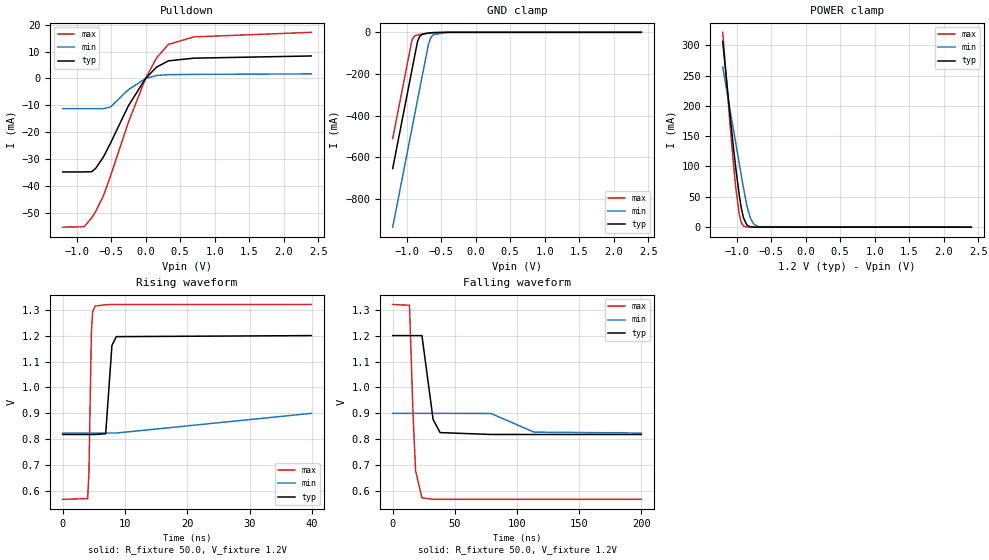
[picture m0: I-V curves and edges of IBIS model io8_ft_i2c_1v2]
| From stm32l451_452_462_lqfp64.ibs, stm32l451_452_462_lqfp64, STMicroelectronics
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[Model]   io8_ft_i2c_1v2
Model_type I/O_open_drain
Polarity   Non-Inverting
Enable   Active-Low
| CAP_THRESHOLD on pad IOFT is "UDTCAPC" :
| Rising=30.00f vddiom   Falling=70.00f vddiom
| C_comp min and max val. don't necessarily correlate with the min and max pvt
| but are the smallest and greatest pad capacitance found.
| var   typ   min   max
C_comp   1.98220pF  1.85370pF  1.99115pF
|C_comp_pulldown   1.98220pF  1.85370pF  1.99115pF
Vinl = 270.0mV
Vinh = 924.0mV
Vmeas = 600.0mV   | Reference voltage for timing measurements
Cref  = 50.0pF   | Timing specification test load capacitance value
Rref  = 100.0MOhm   | Timing specification test load resistance value
Vref  = 1100.0mV   | Timing specification test load voltage
[Model Spec]
| TIME_THRESHOLD on pin ZIV12 is "CMOS" :
| Rising=50.00f vdd   Falling=50.00f vdd
Vinl 458.70000mV 364.70000mV 499.70000mV
Vinh 728.30000mV 548.30000mV 792.30000mV
| variable   typ   min   max
[Temperature Range] 25.0 140.0 -40.0
| variable   typ   min   max
[Voltage Range] 1.2V 900.0mV 1.32V
| variable   typ   min   max
[POWER Clamp Reference] 1.2V 900.0mV 1.32V
| variable   typ   min   max
[GND Clamp Reference] 0V 0V 0V
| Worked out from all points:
|   slope of the pulldown table from 0 to 0.18 V, typ, clamps not added: 39.2 ohm
|   GND clamp passes 1 mA (typ) near -0.58 V on its own axis
|   POWER clamp passes 1 mA (typ) near -0.81 V on its own axis
|   rising waveform, R_fixture 50.0, V_fixture 1.2V: 20-80 % time 530ps typ, 1.7ns min, 320ps max; typ from 0.818 V to 1.2 V
|   falling waveform, R_fixture 50.0, V_fixture 1.2V: 20-80 % time 5.96ns typ, 18.4ns min, 3.27ns max; typ from 1.2 V to 0.818 V
[POWER Clamp]
-1.2V     306.2mA    263.9mA    321.2mA
-1.09V    180mA      191mA      163.4mA
-1.05V    136.9mA    164.5mA    110.9mA
-1.01V    96.55mA    138mA      64.02mA
-960mV    52.29mA    104.9mA    20.68mA
-930mV    31.08mA    85.01mA    7.282mA
-900mV    15.67mA    65.13mA    2.025mA
-850mV    3.417mA    35.2mA     196.2uA
-800mV    570.2uA    14.97mA    18.13uA
-750mV    88.98uA    4.952mA    1.667uA
-680mV    6.495uA    823.9uA    58.96nA
2.4V      0A         0A         0A
[GND Clamp]
-1.2V     -654.2mA   -935.9mA   -510.5mA
-930mV    -195.2mA   -476.9mA   -51.51mA
-910mV    -161.2mA   -442.9mA   -29.29mA
-880mV    -110.2mA   -391.9mA   -17.2mA
-840mV    -43.84mA   -323.9mA   -12.07mA
-810mV    -19.76mA   -272.9mA   -10.01mA
-770mV    -9.108mA   -204.9mA   -7.791mA
-680mV    -3.259mA   -54.03mA   -3.717mA
-650mV    -2.37mA    -26.61mA   -2.656mA
-610mV    -1.452mA   -11.03mA   -1.525mA
-410mV    -14.56uA   -155.6uA   -4.989uA
2.4V      305.2pA    78.85nA    206.8pA
| variable   typ   min   max
[Pullup Reference] 1.2V 900.0mV 1.32V
| variable   typ   min   max
[Pulldown Reference] 0V 0V 0V
[Pulldown]
-1.2V     -34.72mA   -11.22mA   -55.23mA
-890mV    -34.72mA   -11.22mA   -55.08mA
-780mV    -34.63mA   -11.22mA   -51.75mA
-720mV    -33.33mA   -11.22mA   -49.3mA
-610mV    -29.15mA   -11.22mA   -43.53mA
-510mV    -24.14mA   -10.64mA   -36.44mA
-250mV    -10.22mA   -4.195mA   -16.35mA
0V        -15fA      0A         0A
160mV     4.214mA    1.107mA    7.682mA
330mV     6.533mA    1.402mA    12.63mA
700mV     7.534mA    1.5mA      15.43mA
2.4V      8.351mA    1.695mA    17.13mA
[Ramp]
dV/dt_r 228.93255mV/521.99238ps 45.53632mV/1.70191ns 451.08364mV/309.09474ps
dV/dt_f 228.98048mV/5.9597ns 45.59322mV/18.44406ns 451.09592mV/3.27161ns
R_load = 50.0
| Removed startup time: 0s 0s 0s  .
| Removed end time: 39.9ns.
[Rising Waveform]
R_fixture   = 50.0
V_fixture   = 1.2V
V_fixture_min = 900.0mV
V_fixture_max = 1.32V
0s        818.4mV    824mV      568.2mV
4ns       818.3mV    824mV      570.9mV
4.2ns     818.3mV    824mV      663.3mV
4.6ns     818.3mV    824mV      1.208V
4.8ns     818.4mV    824mV      1.291V
5.2ns     818.4mV    824mV      1.314V
6.9ns     821.4mV    824mV      1.319V
7.9ns     1.162V     824mV      1.32V
8.6ns     1.196V     824mV      1.32V
39.9ns    1.2V       899.9mV    1.32V
| Removed startup time: 0s 0s 0s  .
| Removed end time: 199.9ns.
[Falling Waveform]
R_fixture   = 50.0
V_fixture   = 1.2V
V_fixture_min = 900.0mV
V_fixture_max = 1.32V
0s        1.2V       900mV      1.32V
13.5ns    1.2V       900mV      1.317V
16.3ns    1.2V       900mV      901.5mV
18.4ns    1.2V       900mV      678.1mV
23.5ns    1.2V       900mV      573.9mV
32.5ns    875.9mV    900mV      568.2mV
38.1ns    825.7mV    900mV      568.2mV
79ns      818.5mV    899.5mV    568.2mV
113.6ns   818.4mV    827.5mV    568.2mV
199.9ns   818.4mV    824mV      568.2mV
